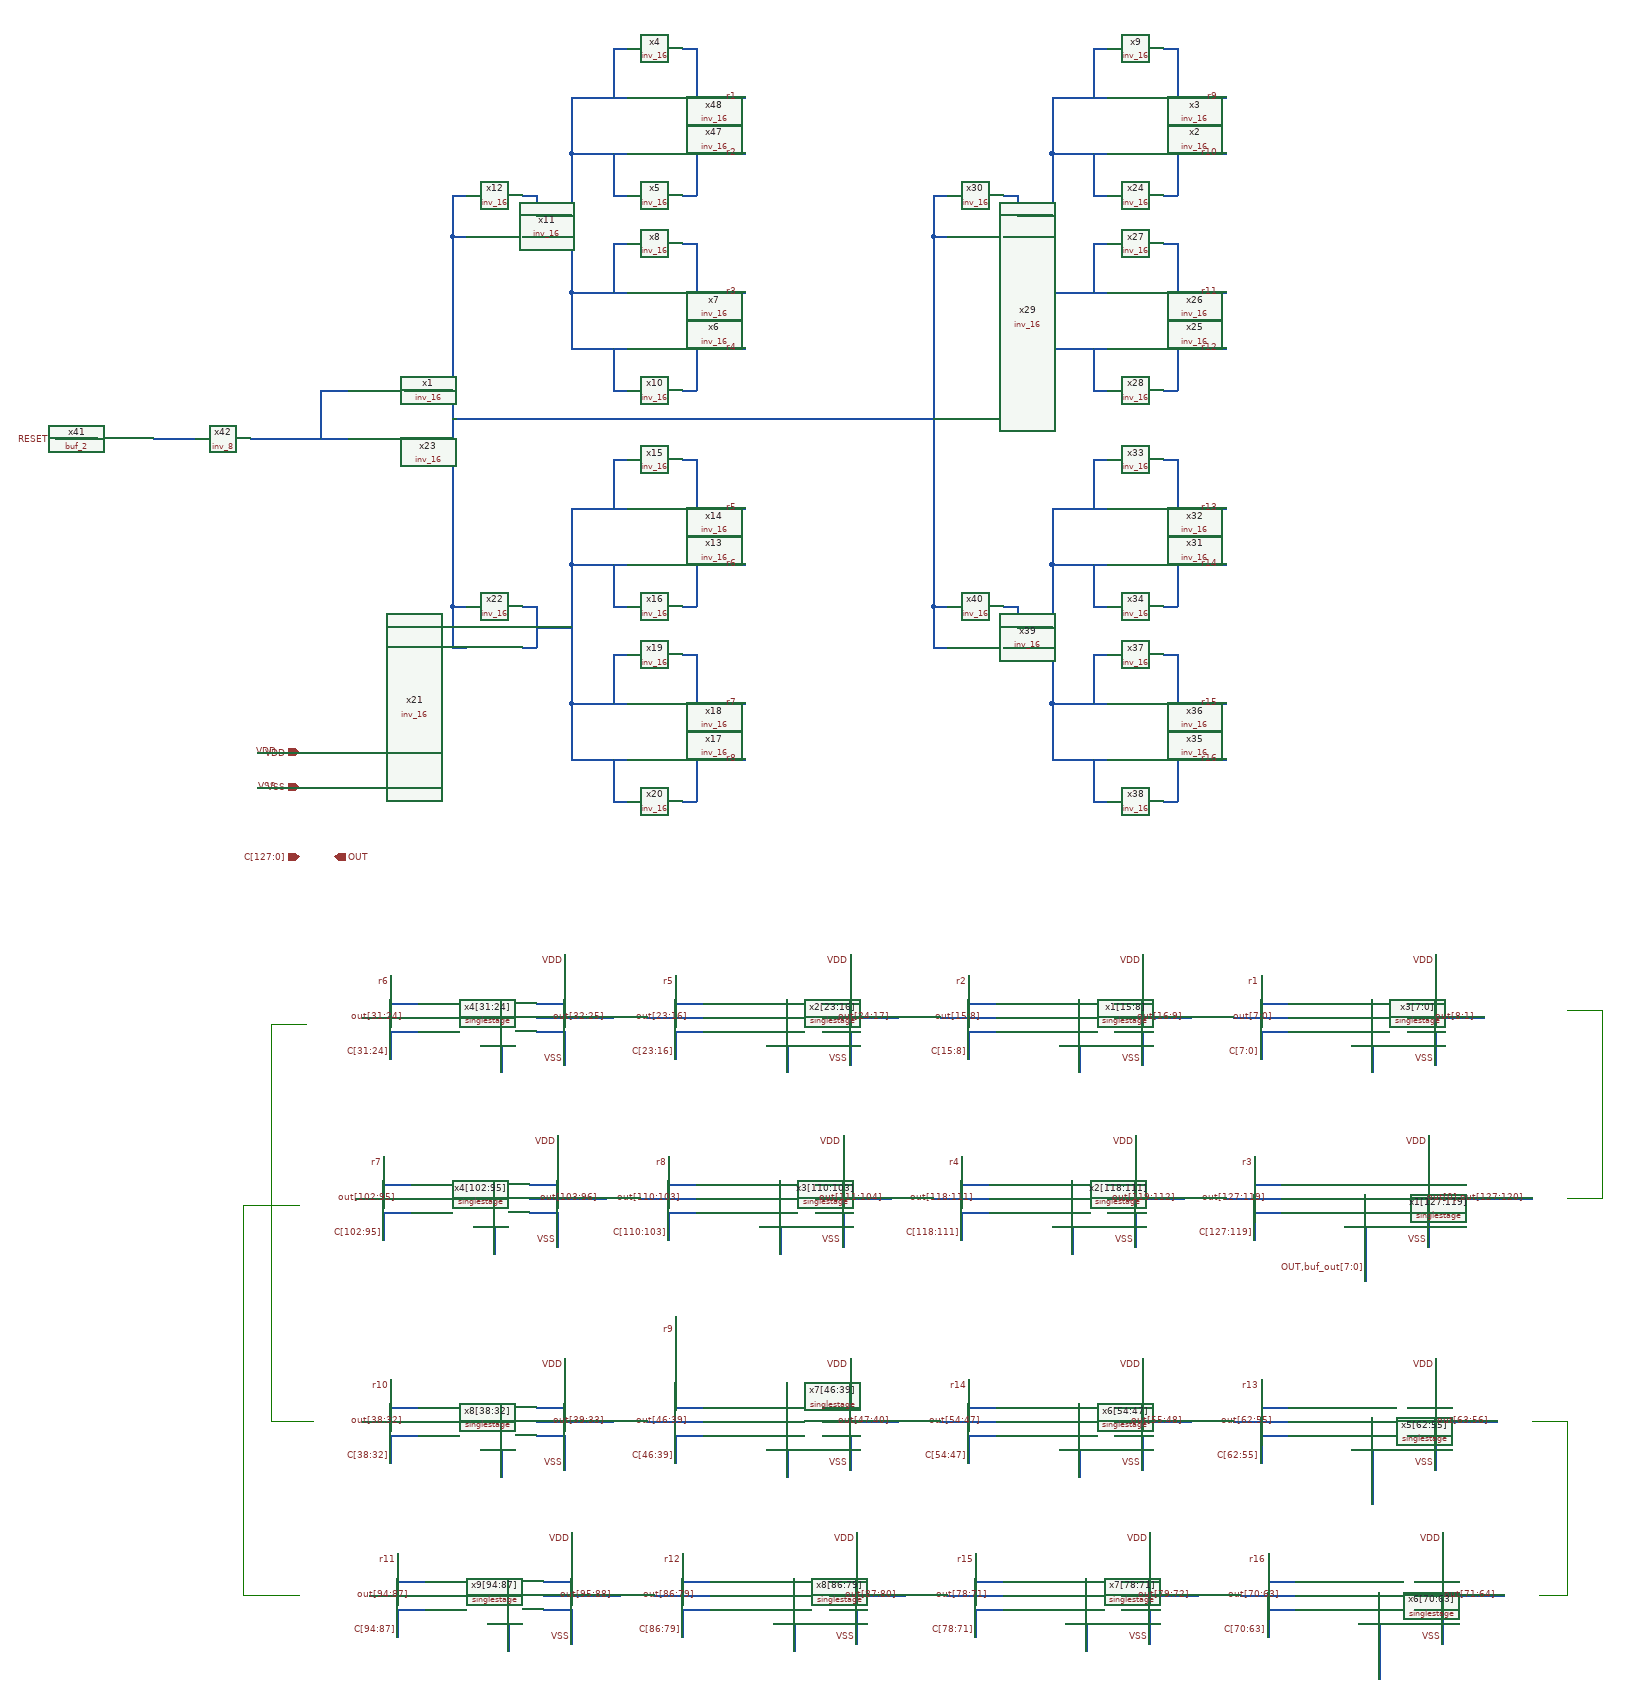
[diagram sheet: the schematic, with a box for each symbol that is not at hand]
v {xschem version=3.0.0 file_version=1.2 }
G {}
K {}
V {}
S {}
E {}
L 4 -280 200 -200 200 {}
L 4 -280 200 -280 760 {}
L 4 -280 760 -210 760 {}
L 4 -210 760 -200 760 {}
L 4 -240 510 -180 510 {}
L 4 -240 -60 -240 510 {}
L 4 -240 -60 -190 -60 {}
L 4 1570 510 1620 510 {}
L 4 1620 510 1620 760 {}
L 4 1580 760 1620 760 {}
L 4 1620 190 1670 190 {}
L 4 1670 -80 1670 190 {}
L 4 1620 -80 1670 -80 {}
N -260 -450 -190 -450 { lab=VDD}
N -260 -400 -190 -400 { lab=VSS}
N 190 -1390 190 -1330 { lab=#net1}
N 190 -1390 270 -1390 { lab=#net1}
N 190 -1330 190 -1310 { lab=#net1}
N 190 -1310 270 -1310 { lab=#net1}
N 350 -1390 400 -1390 { lab=r1}
N 350 -1310 390 -1310 { lab=r2}
N -550 -900 -490 -900 { lab=RESET}
N 350 -1460 370 -1460 { lab=r1}
N 370 -1460 370 -1390 { lab=r1}
N 250 -1460 270 -1460 { lab=#net1}
N 250 -1460 250 -1390 { lab=#net1}
N 400 -1390 430 -1390 { lab=r1}
N 430 -1390 440 -1390 { lab=r1}
N 390 -1310 440 -1310 { lab=r2}
N 250 -1250 270 -1250 { lab=#net1}
N 250 -1310 250 -1250 { lab=#net1}
N 350 -1250 370 -1250 { lab=r2}
N 370 -1310 370 -1250 { lab=r2}
N 190 -1110 190 -1050 { lab=#net1}
N 190 -1110 270 -1110 { lab=#net1}
N 190 -1050 190 -1030 { lab=#net1}
N 190 -1030 270 -1030 { lab=#net1}
N 350 -1110 400 -1110 { lab=r3}
N 350 -1030 390 -1030 { lab=r4}
N 350 -1180 370 -1180 { lab=r3}
N 370 -1180 370 -1110 { lab=r3}
N 250 -1180 270 -1180 { lab=#net1}
N 250 -1180 250 -1110 { lab=#net1}
N 400 -1110 430 -1110 { lab=r3}
N 430 -1110 440 -1110 { lab=r3}
N 390 -1030 440 -1030 { lab=r4}
N 250 -970 270 -970 { lab=#net1}
N 250 -1030 250 -970 { lab=#net1}
N 350 -970 370 -970 { lab=r4}
N 370 -1030 370 -970 { lab=r4}
N 190 -1310 190 -1110 { lab=#net1}
N 120 -1250 140 -1250 { lab=#net1}
N 140 -1250 140 -1190 { lab=#net1}
N 120 -1190 140 -1190 { lab=#net1}
N 20 -1190 40 -1190 { lab=#net2}
N 20 -1250 20 -1190 { lab=#net2}
N 20 -1250 40 -1250 { lab=#net2}
N 140 -1220 190 -1220 { lab=#net1}
N 190 -800 190 -740 { lab=#net3}
N 190 -800 270 -800 { lab=#net3}
N 190 -740 190 -720 { lab=#net3}
N 190 -720 270 -720 { lab=#net3}
N 350 -800 400 -800 { lab=r5}
N 350 -720 390 -720 { lab=r6}
N 350 -870 370 -870 { lab=r5}
N 370 -870 370 -800 { lab=r5}
N 250 -870 270 -870 { lab=#net3}
N 250 -870 250 -800 { lab=#net3}
N 400 -800 430 -800 { lab=r5}
N 430 -800 440 -800 { lab=r5}
N 390 -720 440 -720 { lab=r6}
N 250 -660 270 -660 { lab=#net3}
N 250 -720 250 -660 { lab=#net3}
N 350 -660 370 -660 { lab=r6}
N 370 -720 370 -660 { lab=r6}
N 190 -520 190 -460 { lab=#net3}
N 190 -520 270 -520 { lab=#net3}
N 190 -460 190 -440 { lab=#net3}
N 190 -440 270 -440 { lab=#net3}
N 350 -520 400 -520 { lab=r7}
N 350 -440 390 -440 { lab=r8}
N 350 -590 370 -590 { lab=r7}
N 370 -590 370 -520 { lab=r7}
N 250 -590 270 -590 { lab=#net3}
N 250 -590 250 -520 { lab=#net3}
N 400 -520 430 -520 { lab=r7}
N 430 -520 440 -520 { lab=r7}
N 390 -440 440 -440 { lab=r8}
N 250 -380 270 -380 { lab=#net3}
N 250 -440 250 -380 { lab=#net3}
N 350 -380 370 -380 { lab=r8}
N 370 -440 370 -380 { lab=r8}
N 190 -720 190 -520 { lab=#net3}
N 120 -660 140 -660 { lab=#net3}
N 140 -660 140 -600 { lab=#net3}
N 120 -600 140 -600 { lab=#net3}
N 20 -600 40 -600 { lab=#net2}
N 20 -660 20 -600 { lab=#net2}
N 20 -660 40 -660 { lab=#net2}
N 140 -630 190 -630 { lab=#net3}
N 20 -1190 20 -660 { lab=#net2}
N -50 -900 20 -900 { lab=#net2}
N 1390 -70 1460 -70 { lab=out[8:1]}
N 1390 -90 1430 -90 { lab=VDD}
N 1430 -130 1430 -90 { lab=VDD}
N 1390 -50 1430 -50 { lab=VSS}
N 1430 -50 1430 -20 { lab=VSS}
N 1310 -30 1340 -30 { lab=#net4}
N 1340 -30 1340 10 { lab=#net4}
N 1180 -90 1220 -90 { lab=r1}
N 1180 -70 1220 -70 { lab=out[7:0]}
N 1180 -50 1220 -50 { lab=C[7:0]}
N 1430 -160 1430 -130 { lab=VDD}
N 1430 -20 1430 0 { lab=VSS}
N 1460 -70 1500 -70 { lab=out[8:1]}
N 1140 -70 1180 -70 { lab=out[7:0]}
N 1180 -50 1180 -10 { lab=C[7:0]}
N 1180 -130 1180 -90 { lab=r1}
N 970 -70 1040 -70 { lab=out[16:9]}
N 970 -90 1010 -90 { lab=VDD}
N 1010 -130 1010 -90 { lab=VDD}
N 970 -50 1010 -50 { lab=VSS}
N 1010 -50 1010 -20 { lab=VSS}
N 890 -30 920 -30 { lab=#net5}
N 920 -30 920 10 { lab=#net5}
N 760 -90 800 -90 { lab=r2}
N 760 -70 800 -70 { lab=out[15:8]}
N 760 -50 800 -50 { lab=C[15:8]}
N 1010 -160 1010 -130 { lab=VDD}
N 1010 -20 1010 0 { lab=VSS}
N 1040 -70 1080 -70 { lab=out[16:9]}
N 720 -70 760 -70 { lab=out[15:8]}
N 760 -50 760 -10 { lab=C[15:8]}
N 760 -130 760 -90 { lab=r2}
N 550 -70 620 -70 { lab=out[24:17]}
N 550 -90 590 -90 { lab=VDD}
N 590 -130 590 -90 { lab=VDD}
N 550 -50 590 -50 { lab=VSS}
N 590 -50 590 -20 { lab=VSS}
N 470 -30 500 -30 { lab=#net6}
N 500 -30 500 10 { lab=#net6}
N 340 -90 380 -90 { lab=r5}
N 340 -70 380 -70 { lab=out[23:16]}
N 340 -50 380 -50 { lab=C[23:16]}
N 590 -160 590 -130 { lab=VDD}
N 590 -20 590 0 { lab=VSS}
N 620 -70 660 -70 { lab=out[24:17]}
N 300 -70 340 -70 { lab=out[23:16]}
N 340 -50 340 -10 { lab=C[23:16]}
N 340 -130 340 -90 { lab=r5}
N 140 -70 210 -70 { lab=out[32:25]}
N 140 -90 180 -90 { lab=VDD}
N 180 -130 180 -90 { lab=VDD}
N 140 -50 180 -50 { lab=VSS}
N 180 -50 180 -20 { lab=VSS}
N 60 -30 90 -30 { lab=#net7}
N 90 -30 90 10 { lab=#net7}
N -70 -90 -30 -90 { lab=r6}
N -70 -70 -30 -70 { lab=out[31:24]}
N -70 -50 -30 -50 { lab=C[31:24]}
N 180 -160 180 -130 { lab=VDD}
N 180 -20 180 0 { lab=VSS}
N 210 -70 250 -70 { lab=out[32:25]}
N -110 -70 -70 -70 { lab=out[31:24]}
N -70 -50 -70 -10 { lab=C[31:24]}
N -70 -130 -70 -90 { lab=r6}
N 1390 510 1460 510 { lab=out[64:57]}
N 1390 490 1430 490 { lab=VDD}
N 1430 450 1430 490 { lab=VDD}
N 1390 530 1430 530 { lab=VSS}
N 1430 530 1430 560 { lab=VSS}
N 1310 550 1340 550 { lab=#net8}
N 1340 550 1340 590 { lab=#net8}
N 1180 490 1220 490 { lab=r13}
N 1180 510 1220 510 { lab=out[63:56]}
N 1180 530 1220 530 { lab=C[63:56]}
N 1430 420 1430 450 { lab=VDD}
N 1430 560 1430 580 { lab=VSS}
N 1460 510 1500 510 { lab=out[64:57]}
N 1140 510 1180 510 { lab=out[63:56]}
N 1180 530 1180 570 { lab=C[63:56]}
N 1180 450 1180 490 { lab=r13}
N 970 510 1040 510 { lab=out[56:49]}
N 970 490 1010 490 { lab=VDD}
N 1010 450 1010 490 { lab=VDD}
N 970 530 1010 530 { lab=VSS}
N 1010 530 1010 560 { lab=VSS}
N 890 550 920 550 { lab=#net9}
N 920 550 920 590 { lab=#net9}
N 760 490 800 490 { lab=r14}
N 760 510 800 510 { lab=out[55:48]}
N 760 530 800 530 { lab=C[55:48]}
N 1010 420 1010 450 { lab=VDD}
N 1010 560 1010 580 { lab=VSS}
N 1040 510 1080 510 { lab=out[56:49]}
N 720 510 760 510 { lab=out[55:48]}
N 760 530 760 570 { lab=C[55:48]}
N 760 450 760 490 { lab=r14}
N 550 510 620 510 { lab=out[48:41]}
N 550 490 590 490 { lab=VDD}
N 590 450 590 490 { lab=VDD}
N 550 530 590 530 { lab=VSS}
N 590 530 590 560 { lab=VSS}
N 470 550 500 550 { lab=#net10}
N 500 550 500 590 { lab=#net10}
N 340 490 380 490 { lab=r9}
N 340 510 380 510 { lab=out[47:40]}
N 340 530 380 530 { lab=C[47:40]}
N 590 420 590 450 { lab=VDD}
N 590 560 590 580 { lab=VSS}
N 620 510 660 510 { lab=out[48:41]}
N 300 510 340 510 { lab=out[47:40]}
N 340 530 340 570 { lab=C[47:40]}
N 340 450 340 490 { lab=r9}
N 140 510 210 510 { lab=out[40:33]}
N 140 490 180 490 { lab=VDD}
N 180 450 180 490 { lab=VDD}
N 140 530 180 530 { lab=VSS}
N 180 530 180 560 { lab=VSS}
N 60 550 90 550 { lab=#net11}
N 90 550 90 590 { lab=#net11}
N -70 490 -30 490 { lab=r10}
N -70 510 -30 510 { lab=out[39:32]}
N -70 530 -30 530 { lab=C[39:32]}
N 180 420 180 450 { lab=VDD}
N 180 560 180 580 { lab=VSS}
N 210 510 250 510 { lab=out[40:33]}
N -110 510 -70 510 { lab=out[39:32]}
N -70 530 -70 570 { lab=C[39:32]}
N -70 450 -70 490 { lab=r10}
N 1340 590 1340 630 { lab=#net8}
N -50 -970 20 -970 { lab=#net2}
N 880 -1390 880 -1330 { lab=#net12}
N 880 -1390 960 -1390 { lab=#net12}
N 880 -1330 880 -1310 { lab=#net12}
N 880 -1310 960 -1310 { lab=#net12}
N 1040 -1390 1090 -1390 { lab=r9}
N 1040 -1310 1080 -1310 { lab=r10}
N 1040 -1460 1060 -1460 { lab=r9}
N 1060 -1460 1060 -1390 { lab=r9}
N 940 -1460 960 -1460 { lab=#net12}
N 940 -1460 940 -1390 { lab=#net12}
N 1090 -1390 1120 -1390 { lab=r9}
N 1120 -1390 1130 -1390 { lab=r9}
N 1080 -1310 1130 -1310 { lab=r10}
N 940 -1250 960 -1250 { lab=#net12}
N 940 -1310 940 -1250 { lab=#net12}
N 1040 -1250 1060 -1250 { lab=r10}
N 1060 -1310 1060 -1250 { lab=r10}
N 880 -1110 880 -1050 { lab=#net12}
N 880 -1110 960 -1110 { lab=#net12}
N 880 -1050 880 -1030 { lab=#net12}
N 880 -1030 960 -1030 { lab=#net12}
N 1040 -1110 1090 -1110 { lab=r11}
N 1040 -1030 1080 -1030 { lab=r12}
N 1040 -1180 1060 -1180 { lab=r11}
N 1060 -1180 1060 -1110 { lab=r11}
N 940 -1180 960 -1180 { lab=#net12}
N 940 -1180 940 -1110 { lab=#net12}
N 1090 -1110 1120 -1110 { lab=r11}
N 1120 -1110 1130 -1110 { lab=r11}
N 1080 -1030 1130 -1030 { lab=r12}
N 940 -970 960 -970 { lab=#net12}
N 940 -1030 940 -970 { lab=#net12}
N 1040 -970 1060 -970 { lab=r12}
N 1060 -1030 1060 -970 { lab=r12}
N 880 -1310 880 -1110 { lab=#net12}
N 810 -1250 830 -1250 { lab=#net12}
N 830 -1250 830 -1190 { lab=#net12}
N 810 -1190 830 -1190 { lab=#net12}
N 710 -1190 730 -1190 { lab=#net2}
N 710 -1250 710 -1190 { lab=#net2}
N 710 -1250 730 -1250 { lab=#net2}
N 830 -1220 880 -1220 { lab=#net12}
N 880 -800 880 -740 { lab=#net13}
N 880 -800 960 -800 { lab=#net13}
N 880 -740 880 -720 { lab=#net13}
N 880 -720 960 -720 { lab=#net13}
N 1040 -800 1090 -800 { lab=r13}
N 1040 -720 1080 -720 { lab=r14}
N 1040 -870 1060 -870 { lab=r13}
N 1060 -870 1060 -800 { lab=r13}
N 940 -870 960 -870 { lab=#net13}
N 940 -870 940 -800 { lab=#net13}
N 1090 -800 1120 -800 { lab=r13}
N 1120 -800 1130 -800 { lab=r13}
N 1080 -720 1130 -720 { lab=r14}
N 940 -660 960 -660 { lab=#net13}
N 940 -720 940 -660 { lab=#net13}
N 1040 -660 1060 -660 { lab=r14}
N 1060 -720 1060 -660 { lab=r14}
N 880 -520 880 -460 { lab=#net13}
N 880 -520 960 -520 { lab=#net13}
N 880 -460 880 -440 { lab=#net13}
N 880 -440 960 -440 { lab=#net13}
N 1040 -520 1090 -520 { lab=r15}
N 1040 -440 1080 -440 { lab=r16}
N 1040 -590 1060 -590 { lab=r15}
N 1060 -590 1060 -520 { lab=r15}
N 940 -590 960 -590 { lab=#net13}
N 940 -590 940 -520 { lab=#net13}
N 1090 -520 1120 -520 { lab=r15}
N 1120 -520 1130 -520 { lab=r15}
N 1080 -440 1130 -440 { lab=r16}
N 940 -380 960 -380 { lab=#net13}
N 940 -440 940 -380 { lab=#net13}
N 1040 -380 1060 -380 { lab=r16}
N 1060 -440 1060 -380 { lab=r16}
N 880 -720 880 -520 { lab=#net13}
N 810 -660 830 -660 { lab=#net13}
N 830 -660 830 -600 { lab=#net13}
N 810 -600 830 -600 { lab=#net13}
N 710 -600 730 -600 { lab=#net2}
N 710 -660 710 -600 { lab=#net2}
N 710 -660 730 -660 { lab=#net2}
N 830 -630 880 -630 { lab=#net13}
N 710 -1190 710 -660 { lab=#net2}
N 1500 510 1520 510 { lab=out[64:57]}
N 1400 760 1470 760 { lab=out[72:65]}
N 1400 740 1440 740 { lab=VDD}
N 1440 700 1440 740 { lab=VDD}
N 1400 780 1440 780 { lab=VSS}
N 1440 780 1440 810 { lab=VSS}
N 1320 800 1350 800 { lab=#net14}
N 1350 800 1350 840 { lab=#net14}
N 1190 740 1230 740 { lab=r16}
N 1190 760 1230 760 { lab=out[71:64]}
N 1190 780 1230 780 { lab=C[71:64]}
N 1440 670 1440 700 { lab=VDD}
N 1440 810 1440 830 { lab=VSS}
N 1470 760 1510 760 { lab=out[72:65]}
N 1150 760 1190 760 { lab=out[71:64]}
N 1190 780 1190 820 { lab=C[71:64]}
N 1190 700 1190 740 { lab=r16}
N 980 760 1050 760 { lab=out[80:73]}
N 980 740 1020 740 { lab=VDD}
N 1020 700 1020 740 { lab=VDD}
N 980 780 1020 780 { lab=VSS}
N 1020 780 1020 810 { lab=VSS}
N 900 800 930 800 { lab=#net15}
N 930 800 930 840 { lab=#net15}
N 770 740 810 740 { lab=r15}
N 770 760 810 760 { lab=out[79:72]}
N 770 780 810 780 { lab=C[79:72]}
N 1020 670 1020 700 { lab=VDD}
N 1020 810 1020 830 { lab=VSS}
N 1050 760 1090 760 { lab=out[80:73]}
N 730 760 770 760 { lab=out[79:72]}
N 770 780 770 820 { lab=C[79:72]}
N 770 700 770 740 { lab=r15}
N 560 760 630 760 { lab=out[88:81]}
N 560 740 600 740 { lab=VDD}
N 600 700 600 740 { lab=VDD}
N 560 780 600 780 { lab=VSS}
N 600 780 600 810 { lab=VSS}
N 480 800 510 800 { lab=#net16}
N 510 800 510 840 { lab=#net16}
N 350 740 390 740 { lab=r12}
N 350 760 390 760 { lab=out[87:80]}
N 350 780 390 780 { lab=C[87:80]}
N 600 670 600 700 { lab=VDD}
N 600 810 600 830 { lab=VSS}
N 630 760 670 760 { lab=out[88:81]}
N 310 760 350 760 { lab=out[87:80]}
N 350 780 350 820 { lab=C[87:80]}
N 350 700 350 740 { lab=r12}
N 150 760 220 760 { lab=out[96:89]}
N 150 740 190 740 { lab=VDD}
N 190 700 190 740 { lab=VDD}
N 150 780 190 780 { lab=VSS}
N 190 780 190 810 { lab=VSS}
N 70 800 100 800 { lab=#net17}
N 100 800 100 840 { lab=#net17}
N -60 740 -20 740 { lab=r11}
N -60 760 -20 760 { lab=out[95:88]}
N -60 780 -20 780 { lab=C[95:88]}
N 190 670 190 700 { lab=VDD}
N 190 810 190 830 { lab=VSS}
N 220 760 260 760 { lab=out[96:89]}
N -100 760 -60 760 { lab=out[95:88]}
N -60 780 -60 820 { lab=C[95:88]}
N -60 700 -60 740 { lab=r11}
N 1350 840 1350 880 { lab=#net14}
N 1510 760 1530 760 { lab=out[72:65]}
N 1380 190 1450 190 { lab=out[0],out[127:121]}
N 1380 170 1420 170 { lab=VDD}
N 1420 130 1420 170 { lab=VDD}
N 1380 210 1420 210 { lab=VSS}
N 1420 210 1420 240 { lab=VSS}
N 1300 230 1330 230 { lab=OUT,buf_out[6:0]}
N 1330 230 1330 270 { lab=OUT,buf_out[6:0]}
N 1170 170 1210 170 { lab=r3}
N 1170 190 1210 190 { lab=out[127:120]}
N 1170 210 1210 210 { lab=C[127:120]}
N 1420 100 1420 130 { lab=VDD}
N 1420 240 1420 260 { lab=VSS}
N 1450 190 1490 190 { lab=out[0],out[127:121]}
N 1130 190 1170 190 { lab=out[127:120]}
N 1170 210 1170 250 { lab=C[127:120]}
N 1170 130 1170 170 { lab=r3}
N 960 190 1030 190 { lab=out[120:113]}
N 960 170 1000 170 { lab=VDD}
N 1000 130 1000 170 { lab=VDD}
N 960 210 1000 210 { lab=VSS}
N 1000 210 1000 240 { lab=VSS}
N 880 230 910 230 { lab=#net18}
N 910 230 910 270 { lab=#net18}
N 750 170 790 170 { lab=r4}
N 750 190 790 190 { lab=out[119:112]}
N 750 210 790 210 { lab=C[119:112]}
N 1000 100 1000 130 { lab=VDD}
N 1000 240 1000 260 { lab=VSS}
N 1030 190 1070 190 { lab=out[120:113]}
N 710 190 750 190 { lab=out[119:112]}
N 750 210 750 250 { lab=C[119:112]}
N 750 130 750 170 { lab=r4}
N 540 190 610 190 { lab=out[112:105]}
N 540 170 580 170 { lab=VDD}
N 580 130 580 170 { lab=VDD}
N 540 210 580 210 { lab=VSS}
N 580 210 580 240 { lab=VSS}
N 460 230 490 230 { lab=#net19}
N 490 230 490 270 { lab=#net19}
N 330 170 370 170 { lab=r8}
N 330 190 370 190 { lab=out[111:104]}
N 330 210 370 210 { lab=C[111:104]}
N 580 100 580 130 { lab=VDD}
N 580 240 580 260 { lab=VSS}
N 610 190 650 190 { lab=out[112:105]}
N 290 190 330 190 { lab=out[111:104]}
N 330 210 330 250 { lab=C[111:104]}
N 330 130 330 170 { lab=r8}
N 130 190 200 190 { lab=out[104:97]}
N 130 170 170 170 { lab=VDD}
N 170 130 170 170 { lab=VDD}
N 130 210 170 210 { lab=VSS}
N 170 210 170 240 { lab=VSS}
N 50 230 80 230 { lab=#net20}
N 80 230 80 270 { lab=#net20}
N -80 170 -40 170 { lab=r7}
N -80 190 -40 190 { lab=out[103:96]}
N -80 210 -40 210 { lab=C[103:96]}
N 170 100 170 130 { lab=VDD}
N 170 240 170 260 { lab=VSS}
N 200 190 240 190 { lab=out[104:97]}
N -120 190 -80 190 { lab=out[103:96]}
N -80 210 -80 250 { lab=C[103:96]}
N -80 130 -80 170 { lab=r7}
N 1330 270 1330 310 { lab=OUT,buf_out[6:0]}
N 1490 190 1510 190 { lab=out[0],out[127:121]}
N 20 -930 710 -930 { lab=#net2}
N 1510 190 1570 190 { lab=out[0],out[127:121]}
N -220 -900 -130 -900 { lab=#net21}
N -170 -970 -170 -900 { lab=#net21}
N -170 -970 -130 -970 { lab=#net21}
N -270 -900 -220 -900 { lab=#net21}
N -410 -900 -350 -900 { lab=#net22}
N 340 360 340 450 {}
C {devices/iopin.sym} -200 -450 0 0 {name=p1 lab=VDD}
C {devices/lab_pin.sym} -230 -450 0 0 {name=l23 sig_type=std_logic lab=VDD}
C {devices/iopin.sym} -200 -400 0 0 {name=p2 lab=VSS}
C {devices/lab_pin.sym} -230 -400 0 0 {name=l27 sig_type=std_logic lab=VSS}
C {devices/opin.sym} -150 -300 0 0 {name=p3 lab=OUT}
C {sky130_stdcells/inv_16.sym} 310 -1310 0 0 {name=x47 VGND=VSS VNB=VSS VPB=VDD VPWR=VDD prefix=sky130_fd_sc_hd__ }
C {sky130_stdcells/inv_16.sym} 310 -1390 0 0 {name=x48 VGND=VSS VNB=VSS VPB=VDD VPWR=VDD prefix=sky130_fd_sc_hd__ }
C {devices/lab_pin.sym} 430 -1390 0 0 {name=l3 sig_type=std_logic lab=r1}
C {devices/lab_pin.sym} 430 -1310 0 0 {name=l4 sig_type=std_logic lab=r2}
C {devices/ipin.sym} -200 -300 0 0 {name=p28 lab=C[127:0]}
C {devices/ipin.sym} -540 -900 0 0 {name=p36 lab=RESET}
C {sky130_stdcells/inv_16.sym} 310 -1460 0 0 {name=x4 VGND=VSS VNB=VSS VPB=VDD VPWR=VDD prefix=sky130_fd_sc_hd__ }
C {sky130_stdcells/inv_16.sym} 310 -1250 0 0 {name=x5 VGND=VSS VNB=VSS VPB=VDD VPWR=VDD prefix=sky130_fd_sc_hd__ }
C {sky130_stdcells/inv_16.sym} 310 -1030 0 0 {name=x6 VGND=VSS VNB=VSS VPB=VDD VPWR=VDD prefix=sky130_fd_sc_hd__ }
C {sky130_stdcells/inv_16.sym} 310 -1110 0 0 {name=x7 VGND=VSS VNB=VSS VPB=VDD VPWR=VDD prefix=sky130_fd_sc_hd__ }
C {devices/lab_pin.sym} 430 -1110 0 0 {name=l2 sig_type=std_logic lab=r3}
C {devices/lab_pin.sym} 430 -1030 0 0 {name=l7 sig_type=std_logic lab=r4}
C {sky130_stdcells/inv_16.sym} 310 -1180 0 0 {name=x8 VGND=VSS VNB=VSS VPB=VDD VPWR=VDD prefix=sky130_fd_sc_hd__ }
C {sky130_stdcells/inv_16.sym} 310 -970 0 0 {name=x10 VGND=VSS VNB=VSS VPB=VDD VPWR=VDD prefix=sky130_fd_sc_hd__ }
C {sky130_stdcells/inv_16.sym} 80 -1190 0 0 {name=x11 VGND=VSS VNB=VSS VPB=VDD VPWR=VDD prefix=sky130_fd_sc_hd__ }
C {sky130_stdcells/inv_16.sym} 80 -1250 0 0 {name=x12 VGND=VSS VNB=VSS VPB=VDD VPWR=VDD prefix=sky130_fd_sc_hd__ }
C {sky130_stdcells/inv_16.sym} 310 -720 0 0 {name=x13 VGND=VSS VNB=VSS VPB=VDD VPWR=VDD prefix=sky130_fd_sc_hd__ }
C {sky130_stdcells/inv_16.sym} 310 -800 0 0 {name=x14 VGND=VSS VNB=VSS VPB=VDD VPWR=VDD prefix=sky130_fd_sc_hd__ }
C {devices/lab_pin.sym} 430 -800 0 0 {name=l8 sig_type=std_logic lab=r5}
C {devices/lab_pin.sym} 430 -720 0 0 {name=l9 sig_type=std_logic lab=r6}
C {sky130_stdcells/inv_16.sym} 310 -870 0 0 {name=x15 VGND=VSS VNB=VSS VPB=VDD VPWR=VDD prefix=sky130_fd_sc_hd__ }
C {sky130_stdcells/inv_16.sym} 310 -660 0 0 {name=x16 VGND=VSS VNB=VSS VPB=VDD VPWR=VDD prefix=sky130_fd_sc_hd__ }
C {sky130_stdcells/inv_16.sym} 310 -440 0 0 {name=x17 VGND=VSS VNB=VSS VPB=VDD VPWR=VDD prefix=sky130_fd_sc_hd__ }
C {sky130_stdcells/inv_16.sym} 310 -520 0 0 {name=x18 VGND=VSS VNB=VSS VPB=VDD VPWR=VDD prefix=sky130_fd_sc_hd__ }
C {devices/lab_pin.sym} 430 -520 0 0 {name=l11 sig_type=std_logic lab=r7}
C {devices/lab_pin.sym} 430 -440 0 0 {name=l12 sig_type=std_logic lab=r8}
C {sky130_stdcells/inv_16.sym} 310 -590 0 0 {name=x19 VGND=VSS VNB=VSS VPB=VDD VPWR=VDD prefix=sky130_fd_sc_hd__ }
C {sky130_stdcells/inv_16.sym} 310 -380 0 0 {name=x20 VGND=VSS VNB=VSS VPB=VDD VPWR=VDD prefix=sky130_fd_sc_hd__ }
C {sky130_stdcells/inv_16.sym} 80 -600 0 0 {name=x21 VGND=VSS VNB=VSS VPB=VDD VPWR=VDD prefix=sky130_fd_sc_hd__ }
C {sky130_stdcells/inv_16.sym} 80 -660 0 0 {name=x22 VGND=VSS VNB=VSS VPB=VDD VPWR=VDD prefix=sky130_fd_sc_hd__ }
C {sky130_stdcells/inv_16.sym} -90 -900 0 0 {name=x23 VGND=VSS VNB=VSS VPB=VDD VPWR=VDD prefix=sky130_fd_sc_hd__ }
C {singlestage.sym} 1370 -70 0 0 {name=x3[7:0]}
C {devices/lab_pin.sym} 1430 -150 0 0 {name=l1 sig_type=std_logic lab=VDD}
C {devices/lab_pin.sym} 1430 -10 0 0 {name=l5 sig_type=std_logic lab=VSS}
C {devices/lab_pin.sym} 1490 -70 0 0 {name=l6 sig_type=std_logic lab=out[8:1]}
C {devices/lab_pin.sym} 1200 -70 0 0 {name=l10 sig_type=std_logic lab=out[7:0]}
C {devices/lab_pin.sym} 1180 -20 0 0 {name=l13 sig_type=std_logic lab=C[7:0]}
C {devices/lab_pin.sym} 1180 -120 0 0 {name=l14 sig_type=std_logic lab=r1}
C {singlestage.sym} 950 -70 0 0 {name=x1[15:8]}
C {devices/lab_pin.sym} 1010 -150 0 0 {name=l15 sig_type=std_logic lab=VDD}
C {devices/lab_pin.sym} 1010 -10 0 0 {name=l16 sig_type=std_logic lab=VSS}
C {devices/lab_pin.sym} 1070 -70 0 0 {name=l17 sig_type=std_logic lab=out[16:9]}
C {devices/lab_pin.sym} 780 -70 0 0 {name=l18 sig_type=std_logic lab=out[15:8]}
C {devices/lab_pin.sym} 760 -20 0 0 {name=l19 sig_type=std_logic lab=C[15:8]}
C {devices/lab_pin.sym} 760 -120 0 0 {name=l20 sig_type=std_logic lab=r2}
C {singlestage.sym} 530 -70 0 0 {name=x2[23:16]}
C {devices/lab_pin.sym} 590 -150 0 0 {name=l21 sig_type=std_logic lab=VDD}
C {devices/lab_pin.sym} 590 -10 0 0 {name=l22 sig_type=std_logic lab=VSS}
C {devices/lab_pin.sym} 650 -70 0 0 {name=l24 sig_type=std_logic lab=out[24:17]}
C {devices/lab_pin.sym} 360 -70 0 0 {name=l25 sig_type=std_logic lab=out[23:16]}
C {devices/lab_pin.sym} 340 -20 0 0 {name=l26 sig_type=std_logic lab=C[23:16]}
C {devices/lab_pin.sym} 340 -120 0 0 {name=l28 sig_type=std_logic lab=r5}
C {singlestage.sym} 120 -70 0 0 {name=x4[31:24]}
C {devices/lab_pin.sym} 180 -150 0 0 {name=l29 sig_type=std_logic lab=VDD}
C {devices/lab_pin.sym} 180 -10 0 0 {name=l30 sig_type=std_logic lab=VSS}
C {devices/lab_pin.sym} 240 -70 0 0 {name=l31 sig_type=std_logic lab=out[32:25]}
C {devices/lab_pin.sym} -50 -70 0 0 {name=l32 sig_type=std_logic lab=out[31:24]}
C {devices/lab_pin.sym} -70 -20 0 0 {name=l33 sig_type=std_logic lab=C[31:24]}
C {devices/lab_pin.sym} -70 -120 0 0 {name=l34 sig_type=std_logic lab=r6}
C {singlestage.sym} 1370 510 0 0 {name=x5[62:55]}
C {devices/lab_pin.sym} 1430 430 0 0 {name=l35 sig_type=std_logic lab=VDD}
C {devices/lab_pin.sym} 1430 570 0 0 {name=l36 sig_type=std_logic lab=VSS}
C {devices/lab_pin.sym} 1510 510 0 0 {name=l37 sig_type=std_logic lab=out[63:56]}
C {devices/lab_pin.sym} 1200 510 0 0 {name=l38 sig_type=std_logic lab=out[62:55]}
C {devices/lab_pin.sym} 1180 560 0 0 {name=l39 sig_type=std_logic lab=C[62:55]}
C {devices/lab_pin.sym} 1180 460 0 0 {name=l40 sig_type=std_logic lab=r13}
C {singlestage.sym} 950 510 0 0 {name=x6[54:47]}
C {devices/lab_pin.sym} 1010 430 0 0 {name=l41 sig_type=std_logic lab=VDD}
C {devices/lab_pin.sym} 1010 570 0 0 {name=l42 sig_type=std_logic lab=VSS}
C {devices/lab_pin.sym} 1070 510 0 0 {name=l43 sig_type=std_logic lab=out[55:48]}
C {devices/lab_pin.sym} 780 510 0 0 {name=l44 sig_type=std_logic lab=out[54:47]}
C {devices/lab_pin.sym} 760 560 0 0 {name=l45 sig_type=std_logic lab=C[54:47]}
C {devices/lab_pin.sym} 760 460 0 0 {name=l46 sig_type=std_logic lab=r14}
C {singlestage.sym} 530 510 0 0 {name=x7[46:39]}
C {devices/lab_pin.sym} 590 430 0 0 {name=l79 sig_type=std_logic lab=VDD}
C {devices/lab_pin.sym} 590 570 0 0 {name=l80 sig_type=std_logic lab=VSS}
C {devices/lab_pin.sym} 650 510 0 0 {name=l81 sig_type=std_logic lab=out[47:40]}
C {devices/lab_pin.sym} 360 510 0 0 {name=l82 sig_type=std_logic lab=out[46:39]}
C {devices/lab_pin.sym} 340 560 0 0 {name=l83 sig_type=std_logic lab=C[46:39]}
C {devices/lab_pin.sym} 340 380 0 0 {name=l84 sig_type=std_logic lab=r9}
C {singlestage.sym} 120 510 0 0 {name=x8[38:32]}
C {devices/lab_pin.sym} 180 430 0 0 {name=l85 sig_type=std_logic lab=VDD}
C {devices/lab_pin.sym} 180 570 0 0 {name=l86 sig_type=std_logic lab=VSS}
C {devices/lab_pin.sym} 240 510 0 0 {name=l87 sig_type=std_logic lab=out[39:33]}
C {devices/lab_pin.sym} -50 510 0 0 {name=l88 sig_type=std_logic lab=out[38:32]}
C {devices/lab_pin.sym} -70 560 0 0 {name=l89 sig_type=std_logic lab=C[38:32]}
C {devices/lab_pin.sym} -70 460 0 0 {name=l90 sig_type=std_logic lab=r10}
C {sky130_stdcells/inv_16.sym} -90 -970 0 0 {name=x1 VGND=VSS VNB=VSS VPB=VDD VPWR=VDD prefix=sky130_fd_sc_hd__ }
C {sky130_stdcells/inv_16.sym} 1000 -1310 0 0 {name=x2 VGND=VSS VNB=VSS VPB=VDD VPWR=VDD prefix=sky130_fd_sc_hd__ }
C {sky130_stdcells/inv_16.sym} 1000 -1390 0 0 {name=x3 VGND=VSS VNB=VSS VPB=VDD VPWR=VDD prefix=sky130_fd_sc_hd__ }
C {devices/lab_pin.sym} 1120 -1390 0 0 {name=l48 sig_type=std_logic lab=r9}
C {devices/lab_pin.sym} 1120 -1310 0 0 {name=l49 sig_type=std_logic lab=r10}
C {sky130_stdcells/inv_16.sym} 1000 -1460 0 0 {name=x9 VGND=VSS VNB=VSS VPB=VDD VPWR=VDD prefix=sky130_fd_sc_hd__ }
C {sky130_stdcells/inv_16.sym} 1000 -1250 0 0 {name=x24 VGND=VSS VNB=VSS VPB=VDD VPWR=VDD prefix=sky130_fd_sc_hd__ }
C {sky130_stdcells/inv_16.sym} 1000 -1030 0 0 {name=x25 VGND=VSS VNB=VSS VPB=VDD VPWR=VDD prefix=sky130_fd_sc_hd__ }
C {sky130_stdcells/inv_16.sym} 1000 -1110 0 0 {name=x26 VGND=VSS VNB=VSS VPB=VDD VPWR=VDD prefix=sky130_fd_sc_hd__ }
C {devices/lab_pin.sym} 1120 -1110 0 0 {name=l50 sig_type=std_logic lab=r11}
C {devices/lab_pin.sym} 1120 -1030 0 0 {name=l51 sig_type=std_logic lab=r12}
C {sky130_stdcells/inv_16.sym} 1000 -1180 0 0 {name=x27 VGND=VSS VNB=VSS VPB=VDD VPWR=VDD prefix=sky130_fd_sc_hd__ }
C {sky130_stdcells/inv_16.sym} 1000 -970 0 0 {name=x28 VGND=VSS VNB=VSS VPB=VDD VPWR=VDD prefix=sky130_fd_sc_hd__ }
C {sky130_stdcells/inv_16.sym} 770 -1190 0 0 {name=x29 VGND=VSS VNB=VSS VPB=VDD VPWR=VDD prefix=sky130_fd_sc_hd__ }
C {sky130_stdcells/inv_16.sym} 770 -1250 0 0 {name=x30 VGND=VSS VNB=VSS VPB=VDD VPWR=VDD prefix=sky130_fd_sc_hd__ }
C {sky130_stdcells/inv_16.sym} 1000 -720 0 0 {name=x31 VGND=VSS VNB=VSS VPB=VDD VPWR=VDD prefix=sky130_fd_sc_hd__ }
C {sky130_stdcells/inv_16.sym} 1000 -800 0 0 {name=x32 VGND=VSS VNB=VSS VPB=VDD VPWR=VDD prefix=sky130_fd_sc_hd__ }
C {devices/lab_pin.sym} 1120 -800 0 0 {name=l52 sig_type=std_logic lab=r13}
C {devices/lab_pin.sym} 1120 -720 0 0 {name=l53 sig_type=std_logic lab=r14}
C {sky130_stdcells/inv_16.sym} 1000 -870 0 0 {name=x33 VGND=VSS VNB=VSS VPB=VDD VPWR=VDD prefix=sky130_fd_sc_hd__ }
C {sky130_stdcells/inv_16.sym} 1000 -660 0 0 {name=x34 VGND=VSS VNB=VSS VPB=VDD VPWR=VDD prefix=sky130_fd_sc_hd__ }
C {sky130_stdcells/inv_16.sym} 1000 -440 0 0 {name=x35 VGND=VSS VNB=VSS VPB=VDD VPWR=VDD prefix=sky130_fd_sc_hd__ }
C {sky130_stdcells/inv_16.sym} 1000 -520 0 0 {name=x36 VGND=VSS VNB=VSS VPB=VDD VPWR=VDD prefix=sky130_fd_sc_hd__ }
C {devices/lab_pin.sym} 1120 -520 0 0 {name=l54 sig_type=std_logic lab=r15}
C {devices/lab_pin.sym} 1120 -440 0 0 {name=l55 sig_type=std_logic lab=r16}
C {sky130_stdcells/inv_16.sym} 1000 -590 0 0 {name=x37 VGND=VSS VNB=VSS VPB=VDD VPWR=VDD prefix=sky130_fd_sc_hd__ }
C {sky130_stdcells/inv_16.sym} 1000 -380 0 0 {name=x38 VGND=VSS VNB=VSS VPB=VDD VPWR=VDD prefix=sky130_fd_sc_hd__ }
C {sky130_stdcells/inv_16.sym} 770 -600 0 0 {name=x39 VGND=VSS VNB=VSS VPB=VDD VPWR=VDD prefix=sky130_fd_sc_hd__ }
C {sky130_stdcells/inv_16.sym} 770 -660 0 0 {name=x40 VGND=VSS VNB=VSS VPB=VDD VPWR=VDD prefix=sky130_fd_sc_hd__ }
C {singlestage.sym} 1380 760 0 0 {name=x6[70:63]}
C {devices/lab_pin.sym} 1440 680 0 0 {name=l93 sig_type=std_logic lab=VDD}
C {devices/lab_pin.sym} 1440 820 0 0 {name=l94 sig_type=std_logic lab=VSS}
C {devices/lab_pin.sym} 1520 760 0 0 {name=l95 sig_type=std_logic lab=out[71:64]}
C {devices/lab_pin.sym} 1210 760 0 0 {name=l96 sig_type=std_logic lab=out[70:63]}
C {devices/lab_pin.sym} 1190 810 0 0 {name=l97 sig_type=std_logic lab=C[70:63]}
C {devices/lab_pin.sym} 1190 710 0 0 {name=l98 sig_type=std_logic lab=r16}
C {singlestage.sym} 960 760 0 0 {name=x7[78:71]}
C {devices/lab_pin.sym} 1020 680 0 0 {name=l99 sig_type=std_logic lab=VDD}
C {devices/lab_pin.sym} 1020 820 0 0 {name=l100 sig_type=std_logic lab=VSS}
C {devices/lab_pin.sym} 1080 760 0 0 {name=l101 sig_type=std_logic lab=out[79:72]}
C {devices/lab_pin.sym} 790 760 0 0 {name=l102 sig_type=std_logic lab=out[78:71]}
C {devices/lab_pin.sym} 770 810 0 0 {name=l103 sig_type=std_logic lab=C[78:71]}
C {devices/lab_pin.sym} 770 710 0 0 {name=l104 sig_type=std_logic lab=r15}
C {singlestage.sym} 540 760 0 0 {name=x8[86:79]}
C {devices/lab_pin.sym} 600 680 0 0 {name=l105 sig_type=std_logic lab=VDD}
C {devices/lab_pin.sym} 600 820 0 0 {name=l106 sig_type=std_logic lab=VSS}
C {devices/lab_pin.sym} 660 760 0 0 {name=l107 sig_type=std_logic lab=out[87:80]}
C {devices/lab_pin.sym} 370 760 0 0 {name=l108 sig_type=std_logic lab=out[86:79]}
C {devices/lab_pin.sym} 350 810 0 0 {name=l109 sig_type=std_logic lab=C[86:79]}
C {devices/lab_pin.sym} 350 710 0 0 {name=l110 sig_type=std_logic lab=r12}
C {singlestage.sym} 130 760 0 0 {name=x9[94:87]}
C {devices/lab_pin.sym} 190 680 0 0 {name=l111 sig_type=std_logic lab=VDD}
C {devices/lab_pin.sym} 190 820 0 0 {name=l112 sig_type=std_logic lab=VSS}
C {devices/lab_pin.sym} 250 760 0 0 {name=l113 sig_type=std_logic lab=out[95:88]}
C {devices/lab_pin.sym} -40 760 0 0 {name=l114 sig_type=std_logic lab=out[94:87]}
C {devices/lab_pin.sym} -60 810 0 0 {name=l115 sig_type=std_logic lab=C[94:87]}
C {devices/lab_pin.sym} -60 710 0 0 {name=l116 sig_type=std_logic lab=r11}
C {singlestage.sym} 1360 190 0 0 {name=x1[127:119]}
C {devices/lab_pin.sym} 1420 110 0 0 {name=l57 sig_type=std_logic lab=VDD}
C {devices/lab_pin.sym} 1420 250 0 0 {name=l58 sig_type=std_logic lab=VSS}
C {devices/lab_pin.sym} 1560 190 0 0 {name=l59 sig_type=std_logic lab=out[0],out[127:120]}
C {devices/lab_pin.sym} 1190 190 0 0 {name=l60 sig_type=std_logic lab=out[127:119]}
C {devices/lab_pin.sym} 1170 240 0 0 {name=l61 sig_type=std_logic lab=C[127:119]}
C {devices/lab_pin.sym} 1170 140 0 0 {name=l62 sig_type=std_logic lab=r3}
C {singlestage.sym} 940 190 0 0 {name=x2[118:111]}
C {devices/lab_pin.sym} 1000 110 0 0 {name=l63 sig_type=std_logic lab=VDD}
C {devices/lab_pin.sym} 1000 250 0 0 {name=l64 sig_type=std_logic lab=VSS}
C {devices/lab_pin.sym} 1060 190 0 0 {name=l65 sig_type=std_logic lab=out[119:112]}
C {devices/lab_pin.sym} 770 190 0 0 {name=l66 sig_type=std_logic lab=out[118:111]}
C {devices/lab_pin.sym} 750 240 0 0 {name=l67 sig_type=std_logic lab=C[118:111]}
C {devices/lab_pin.sym} 750 140 0 0 {name=l68 sig_type=std_logic lab=r4}
C {singlestage.sym} 520 190 0 0 {name=x3[110:103]}
C {devices/lab_pin.sym} 580 110 0 0 {name=l69 sig_type=std_logic lab=VDD}
C {devices/lab_pin.sym} 580 250 0 0 {name=l70 sig_type=std_logic lab=VSS}
C {devices/lab_pin.sym} 640 190 0 0 {name=l71 sig_type=std_logic lab=out[111:104]}
C {devices/lab_pin.sym} 350 190 0 0 {name=l72 sig_type=std_logic lab=out[110:103]}
C {devices/lab_pin.sym} 330 240 0 0 {name=l73 sig_type=std_logic lab=C[110:103]}
C {devices/lab_pin.sym} 330 140 0 0 {name=l74 sig_type=std_logic lab=r8}
C {singlestage.sym} 110 190 0 0 {name=x4[102:95]}
C {devices/lab_pin.sym} 170 110 0 0 {name=l75 sig_type=std_logic lab=VDD}
C {devices/lab_pin.sym} 170 250 0 0 {name=l76 sig_type=std_logic lab=VSS}
C {devices/lab_pin.sym} 230 190 0 0 {name=l77 sig_type=std_logic lab=out[103:96]}
C {devices/lab_pin.sym} -60 190 0 0 {name=l78 sig_type=std_logic lab=out[102:95]}
C {devices/lab_pin.sym} -80 240 0 0 {name=l91 sig_type=std_logic lab=C[102:95]}
C {devices/lab_pin.sym} -80 140 0 0 {name=l92 sig_type=std_logic lab=r7}
C {devices/lab_pin.sym} 1330 290 0 0 {name=l117 sig_type=std_logic lab=OUT,buf_out[7:0]}
C {sky130_stdcells/buf_2.sym} -450 -900 0 0 {name=x41 VGND=VSS VNB=VSS VPB=VDD VPWR=VDD prefix=sky130_fd_sc_hd__ }
C {sky130_stdcells/inv_8.sym} -310 -900 0 0 {name=x42 VGND=VSS VNB=VSS VPB=VDD VPWR=VDD prefix=sky130_fd_sc_hd__ }
